VERSION 5.7 ;
  NAMESCASESENSITIVE ON ;
  NOWIREEXTENSIONATPIN ON ;
  DIVIDERCHAR "/" ;
  BUSBITCHARS "[]" ;
UNITS
  DATABASE MICRONS 200 ;
END UNITS

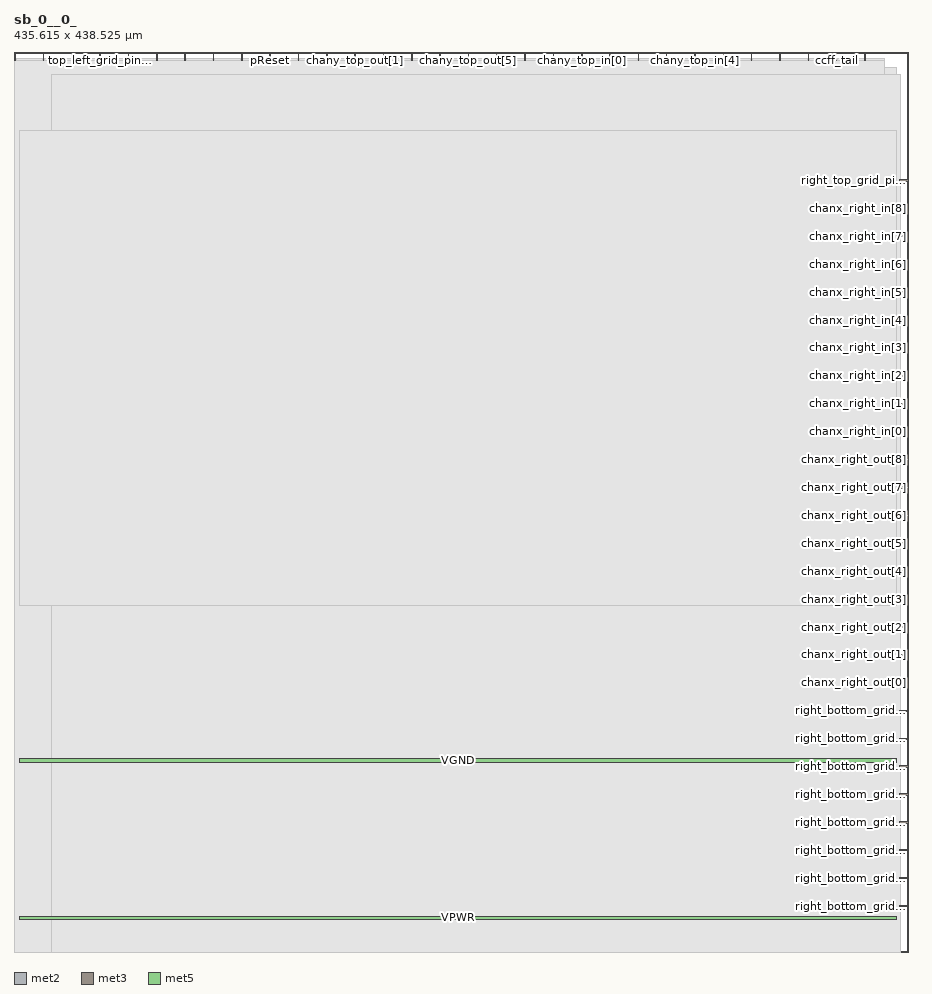
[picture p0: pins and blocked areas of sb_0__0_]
MACRO sb_0__0_
  CLASS BLOCK ;
  FOREIGN sb_0__0_ ;
  ORIGIN 0.000 0.000 ;
  SIZE 435.615 BY 438.525 ;
  PIN ccff_head
    DIRECTION INPUT ;
    PORT
      LAYER met2 ;
        RECT 0.480 434.525 0.760 438.525 ;
    END
  END ccff_head
  PIN top_left_grid_pin_1_
    DIRECTION INPUT ;
    PORT
      LAYER met2 ;
        RECT 14.280 434.525 14.560 438.525 ;
    END
  END top_left_grid_pin_1_
  PIN top_left_grid_pin_3_
    DIRECTION INPUT ;
    PORT
      LAYER met2 ;
        RECT 28.080 434.525 28.360 438.525 ;
    END
  END top_left_grid_pin_3_
  PIN top_left_grid_pin_5_
    DIRECTION INPUT ;
    PORT
      LAYER met2 ;
        RECT 41.880 434.525 42.160 438.525 ;
    END
  END top_left_grid_pin_5_
  PIN top_left_grid_pin_7_
    DIRECTION INPUT ;
    PORT
      LAYER met2 ;
        RECT 55.680 434.525 55.960 438.525 ;
    END
  END top_left_grid_pin_7_
  PIN top_left_grid_pin_9_
    DIRECTION INPUT ;
    PORT
      LAYER met2 ;
        RECT 69.480 434.525 69.760 438.525 ;
    END
  END top_left_grid_pin_9_
  PIN top_left_grid_pin_11_
    DIRECTION INPUT ;
    PORT
      LAYER met2 ;
        RECT 83.280 434.525 83.560 438.525 ;
    END
  END top_left_grid_pin_11_
  PIN top_left_grid_pin_13_
    DIRECTION INPUT ;
    PORT
      LAYER met2 ;
        RECT 97.080 434.525 97.360 438.525 ;
    END
  END top_left_grid_pin_13_
  PIN top_left_grid_pin_15_
    DIRECTION OUTPUT TRISTATE ;
    PORT
      LAYER met2 ;
        RECT 110.880 434.525 111.160 438.525 ;
    END
  END top_left_grid_pin_15_
  PIN pReset
    DIRECTION INPUT ;
    PORT
      LAYER met2 ;
        RECT 124.680 434.525 124.960 438.525 ;
    END
  END pReset
  PIN prog_clk
    DIRECTION INPUT ;
    PORT
      LAYER met2 ;
        RECT 138.480 434.525 138.760 438.525 ;
    END
  END prog_clk
  PIN chany_top_out[0]
    DIRECTION OUTPUT TRISTATE ;
    PORT
      LAYER met2 ;
        RECT 152.280 434.525 152.560 438.525 ;
    END
  END chany_top_out[0]
  PIN chany_top_out[1]
    DIRECTION OUTPUT TRISTATE ;
    PORT
      LAYER met2 ;
        RECT 166.080 434.525 166.360 438.525 ;
    END
  END chany_top_out[1]
  PIN chany_top_out[2]
    DIRECTION OUTPUT TRISTATE ;
    PORT
      LAYER met2 ;
        RECT 179.880 434.525 180.160 438.525 ;
    END
  END chany_top_out[2]
  PIN chany_top_out[3]
    DIRECTION OUTPUT TRISTATE ;
    PORT
      LAYER met2 ;
        RECT 193.680 434.525 193.960 438.525 ;
    END
  END chany_top_out[3]
  PIN chany_top_out[4]
    DIRECTION OUTPUT TRISTATE ;
    PORT
      LAYER met2 ;
        RECT 207.480 434.525 207.760 438.525 ;
    END
  END chany_top_out[4]
  PIN chany_top_out[5]
    DIRECTION OUTPUT TRISTATE ;
    PORT
      LAYER met2 ;
        RECT 221.280 434.525 221.560 438.525 ;
    END
  END chany_top_out[5]
  PIN chany_top_out[6]
    DIRECTION OUTPUT TRISTATE ;
    PORT
      LAYER met2 ;
        RECT 235.080 434.525 235.360 438.525 ;
    END
  END chany_top_out[6]
  PIN chany_top_out[7]
    DIRECTION OUTPUT TRISTATE ;
    PORT
      LAYER met2 ;
        RECT 248.880 434.525 249.160 438.525 ;
    END
  END chany_top_out[7]
  PIN chany_top_out[8]
    DIRECTION OUTPUT TRISTATE ;
    PORT
      LAYER met2 ;
        RECT 262.680 434.525 262.960 438.525 ;
    END
  END chany_top_out[8]
  PIN chany_top_in[0]
    DIRECTION INPUT ;
    PORT
      LAYER met2 ;
        RECT 276.480 434.525 276.760 438.525 ;
    END
  END chany_top_in[0]
  PIN chany_top_in[1]
    DIRECTION INPUT ;
    PORT
      LAYER met2 ;
        RECT 290.280 434.525 290.560 438.525 ;
    END
  END chany_top_in[1]
  PIN chany_top_in[2]
    DIRECTION INPUT ;
    PORT
      LAYER met2 ;
        RECT 304.080 434.525 304.360 438.525 ;
    END
  END chany_top_in[2]
  PIN chany_top_in[3]
    DIRECTION INPUT ;
    PORT
      LAYER met2 ;
        RECT 317.880 434.525 318.160 438.525 ;
    END
  END chany_top_in[3]
  PIN chany_top_in[4]
    DIRECTION INPUT ;
    PORT
      LAYER met2 ;
        RECT 331.680 434.525 331.960 438.525 ;
    END
  END chany_top_in[4]
  PIN chany_top_in[5]
    DIRECTION INPUT ;
    PORT
      LAYER met2 ;
        RECT 345.480 434.525 345.760 438.525 ;
    END
  END chany_top_in[5]
  PIN chany_top_in[6]
    DIRECTION INPUT ;
    PORT
      LAYER met2 ;
        RECT 359.280 434.525 359.560 438.525 ;
    END
  END chany_top_in[6]
  PIN chany_top_in[7]
    DIRECTION INPUT ;
    PORT
      LAYER met2 ;
        RECT 373.080 434.525 373.360 438.525 ;
    END
  END chany_top_in[7]
  PIN chany_top_in[8]
    DIRECTION INPUT ;
    PORT
      LAYER met2 ;
        RECT 386.880 434.525 387.160 438.525 ;
    END
  END chany_top_in[8]
  PIN ccff_tail
    DIRECTION OUTPUT TRISTATE ;
    PORT
      LAYER met2 ;
        RECT 400.680 434.525 400.960 438.525 ;
    END
  END ccff_tail
  PIN top_right_grid_pin_11_
    DIRECTION INPUT ;
    PORT
      LAYER met2 ;
        RECT 414.480 434.525 414.760 438.525 ;
    END
  END top_right_grid_pin_11_
  PIN right_bottom_grid_pin_1_
    DIRECTION INPUT ;
    PORT
      LAYER met3 ;
        RECT 431.615 22.040 435.615 22.640 ;
    END
  END right_bottom_grid_pin_1_
  PIN right_bottom_grid_pin_3_
    DIRECTION INPUT ;
    PORT
      LAYER met3 ;
        RECT 431.615 35.640 435.615 36.240 ;
    END
  END right_bottom_grid_pin_3_
  PIN right_bottom_grid_pin_5_
    DIRECTION INPUT ;
    PORT
      LAYER met3 ;
        RECT 431.615 49.240 435.615 49.840 ;
    END
  END right_bottom_grid_pin_5_
  PIN right_bottom_grid_pin_7_
    DIRECTION INPUT ;
    PORT
      LAYER met3 ;
        RECT 431.615 62.840 435.615 63.440 ;
    END
  END right_bottom_grid_pin_7_
  PIN right_bottom_grid_pin_9_
    DIRECTION INPUT ;
    PORT
      LAYER met3 ;
        RECT 431.615 76.440 435.615 77.040 ;
    END
  END right_bottom_grid_pin_9_
  PIN right_bottom_grid_pin_11_
    DIRECTION INPUT ;
    PORT
      LAYER met3 ;
        RECT 431.615 90.040 435.615 90.640 ;
    END
  END right_bottom_grid_pin_11_
  PIN right_bottom_grid_pin_13_
    DIRECTION INPUT ;
    PORT
      LAYER met3 ;
        RECT 431.615 103.640 435.615 104.240 ;
    END
  END right_bottom_grid_pin_13_
  PIN right_bottom_grid_pin_15_
    DIRECTION INPUT ;
    PORT
      LAYER met3 ;
        RECT 431.615 117.240 435.615 117.840 ;
    END
  END right_bottom_grid_pin_15_
  PIN chanx_right_out[0]
    DIRECTION OUTPUT TRISTATE ;
    PORT
      LAYER met3 ;
        RECT 431.615 130.840 435.615 131.440 ;
    END
  END chanx_right_out[0]
  PIN chanx_right_out[1]
    DIRECTION OUTPUT TRISTATE ;
    PORT
      LAYER met3 ;
        RECT 431.615 144.440 435.615 145.040 ;
    END
  END chanx_right_out[1]
  PIN chanx_right_out[2]
    DIRECTION OUTPUT TRISTATE ;
    PORT
      LAYER met3 ;
        RECT 431.615 158.040 435.615 158.640 ;
    END
  END chanx_right_out[2]
  PIN chanx_right_out[3]
    DIRECTION OUTPUT TRISTATE ;
    PORT
      LAYER met3 ;
        RECT 431.615 171.640 435.615 172.240 ;
    END
  END chanx_right_out[3]
  PIN chanx_right_out[4]
    DIRECTION OUTPUT TRISTATE ;
    PORT
      LAYER met3 ;
        RECT 431.615 185.240 435.615 185.840 ;
    END
  END chanx_right_out[4]
  PIN chanx_right_out[5]
    DIRECTION OUTPUT TRISTATE ;
    PORT
      LAYER met3 ;
        RECT 431.615 198.840 435.615 199.440 ;
    END
  END chanx_right_out[5]
  PIN chanx_right_out[6]
    DIRECTION OUTPUT TRISTATE ;
    PORT
      LAYER met3 ;
        RECT 431.615 212.440 435.615 213.040 ;
    END
  END chanx_right_out[6]
  PIN chanx_right_out[7]
    DIRECTION OUTPUT TRISTATE ;
    PORT
      LAYER met3 ;
        RECT 431.615 226.040 435.615 226.640 ;
    END
  END chanx_right_out[7]
  PIN chanx_right_out[8]
    DIRECTION OUTPUT TRISTATE ;
    PORT
      LAYER met3 ;
        RECT 431.615 239.640 435.615 240.240 ;
    END
  END chanx_right_out[8]
  PIN chanx_right_in[0]
    DIRECTION INPUT ;
    PORT
      LAYER met3 ;
        RECT 431.615 253.240 435.615 253.840 ;
    END
  END chanx_right_in[0]
  PIN chanx_right_in[1]
    DIRECTION INPUT ;
    PORT
      LAYER met3 ;
        RECT 431.615 266.840 435.615 267.440 ;
    END
  END chanx_right_in[1]
  PIN chanx_right_in[2]
    DIRECTION INPUT ;
    PORT
      LAYER met3 ;
        RECT 431.615 280.440 435.615 281.040 ;
    END
  END chanx_right_in[2]
  PIN chanx_right_in[3]
    DIRECTION INPUT ;
    PORT
      LAYER met3 ;
        RECT 431.615 294.040 435.615 294.640 ;
    END
  END chanx_right_in[3]
  PIN chanx_right_in[4]
    DIRECTION INPUT ;
    PORT
      LAYER met3 ;
        RECT 431.615 307.640 435.615 308.240 ;
    END
  END chanx_right_in[4]
  PIN chanx_right_in[5]
    DIRECTION INPUT ;
    PORT
      LAYER met3 ;
        RECT 431.615 321.240 435.615 321.840 ;
    END
  END chanx_right_in[5]
  PIN chanx_right_in[6]
    DIRECTION INPUT ;
    PORT
      LAYER met3 ;
        RECT 431.615 334.840 435.615 335.440 ;
    END
  END chanx_right_in[6]
  PIN chanx_right_in[7]
    DIRECTION INPUT ;
    PORT
      LAYER met3 ;
        RECT 431.615 348.440 435.615 349.040 ;
    END
  END chanx_right_in[7]
  PIN chanx_right_in[8]
    DIRECTION INPUT ;
    PORT
      LAYER met3 ;
        RECT 431.615 362.040 435.615 362.640 ;
    END
  END chanx_right_in[8]
  PIN right_top_grid_pin_10_
    DIRECTION INPUT ;
    PORT
      LAYER met3 ;
        RECT 431.615 375.640 435.615 376.240 ;
    END
  END right_top_grid_pin_10_
  PIN VPWR
    DIRECTION INPUT ;
    USE POWER ;
    PORT
      LAYER met5 ;
        RECT 2.690 15.850 430.030 17.450 ;
    END
  END VPWR
  PIN VGND
    DIRECTION INPUT ;
    USE GROUND ;
    PORT
      LAYER met5 ;
        RECT 2.690 92.440 430.030 94.040 ;
    END
  END VGND
  OBS
      LAYER li1 ;
        RECT 2.690 0.155 430.030 427.365 ;
      LAYER met1 ;
        RECT 0.000 0.000 430.030 430.980 ;
      LAYER met2 ;
        RECT 0.030 434.245 0.200 435.170 ;
        RECT 1.040 434.245 14.000 435.170 ;
        RECT 14.840 434.245 27.800 435.170 ;
        RECT 28.640 434.245 41.600 435.170 ;
        RECT 42.440 434.245 55.400 435.170 ;
        RECT 56.240 434.245 69.200 435.170 ;
        RECT 70.040 434.245 83.000 435.170 ;
        RECT 83.840 434.245 96.800 435.170 ;
        RECT 97.640 434.245 110.600 435.170 ;
        RECT 111.440 434.245 124.400 435.170 ;
        RECT 125.240 434.245 138.200 435.170 ;
        RECT 139.040 434.245 152.000 435.170 ;
        RECT 152.840 434.245 165.800 435.170 ;
        RECT 166.640 434.245 179.600 435.170 ;
        RECT 180.440 434.245 193.400 435.170 ;
        RECT 194.240 434.245 207.200 435.170 ;
        RECT 208.040 434.245 221.000 435.170 ;
        RECT 221.840 434.245 234.800 435.170 ;
        RECT 235.640 434.245 248.600 435.170 ;
        RECT 249.440 434.245 262.400 435.170 ;
        RECT 263.240 434.245 276.200 435.170 ;
        RECT 277.040 434.245 290.000 435.170 ;
        RECT 290.840 434.245 303.800 435.170 ;
        RECT 304.640 434.245 317.600 435.170 ;
        RECT 318.440 434.245 331.400 435.170 ;
        RECT 332.240 434.245 345.200 435.170 ;
        RECT 346.040 434.245 359.000 435.170 ;
        RECT 359.840 434.245 372.800 435.170 ;
        RECT 373.640 434.245 386.600 435.170 ;
        RECT 387.440 434.245 400.400 435.170 ;
        RECT 401.240 434.245 414.200 435.170 ;
        RECT 415.040 434.245 423.960 435.170 ;
        RECT 0.030 0.000 423.960 434.245 ;
      LAYER met3 ;
        RECT 18.210 376.640 432.060 427.445 ;
        RECT 18.210 375.240 431.215 376.640 ;
        RECT 18.210 363.040 432.060 375.240 ;
        RECT 18.210 361.640 431.215 363.040 ;
        RECT 18.210 349.440 432.060 361.640 ;
        RECT 18.210 348.040 431.215 349.440 ;
        RECT 18.210 335.840 432.060 348.040 ;
        RECT 18.210 334.440 431.215 335.840 ;
        RECT 18.210 322.240 432.060 334.440 ;
        RECT 18.210 320.840 431.215 322.240 ;
        RECT 18.210 308.640 432.060 320.840 ;
        RECT 18.210 307.240 431.215 308.640 ;
        RECT 18.210 295.040 432.060 307.240 ;
        RECT 18.210 293.640 431.215 295.040 ;
        RECT 18.210 281.440 432.060 293.640 ;
        RECT 18.210 280.040 431.215 281.440 ;
        RECT 18.210 267.840 432.060 280.040 ;
        RECT 18.210 266.440 431.215 267.840 ;
        RECT 18.210 254.240 432.060 266.440 ;
        RECT 18.210 252.840 431.215 254.240 ;
        RECT 18.210 240.640 432.060 252.840 ;
        RECT 18.210 239.240 431.215 240.640 ;
        RECT 18.210 227.040 432.060 239.240 ;
        RECT 18.210 225.640 431.215 227.040 ;
        RECT 18.210 213.440 432.060 225.640 ;
        RECT 18.210 212.040 431.215 213.440 ;
        RECT 18.210 199.840 432.060 212.040 ;
        RECT 18.210 198.440 431.215 199.840 ;
        RECT 18.210 186.240 432.060 198.440 ;
        RECT 18.210 184.840 431.215 186.240 ;
        RECT 18.210 172.640 432.060 184.840 ;
        RECT 18.210 171.240 431.215 172.640 ;
        RECT 18.210 159.040 432.060 171.240 ;
        RECT 18.210 157.640 431.215 159.040 ;
        RECT 18.210 145.440 432.060 157.640 ;
        RECT 18.210 144.040 431.215 145.440 ;
        RECT 18.210 131.840 432.060 144.040 ;
        RECT 18.210 130.440 431.215 131.840 ;
        RECT 18.210 118.240 432.060 130.440 ;
        RECT 18.210 116.840 431.215 118.240 ;
        RECT 18.210 104.640 432.060 116.840 ;
        RECT 18.210 103.240 431.215 104.640 ;
        RECT 18.210 91.040 432.060 103.240 ;
        RECT 18.210 89.640 431.215 91.040 ;
        RECT 18.210 77.440 432.060 89.640 ;
        RECT 18.210 76.040 431.215 77.440 ;
        RECT 18.210 63.840 432.060 76.040 ;
        RECT 18.210 62.440 431.215 63.840 ;
        RECT 18.210 50.240 432.060 62.440 ;
        RECT 18.210 48.840 431.215 50.240 ;
        RECT 18.210 36.640 432.060 48.840 ;
        RECT 18.210 35.240 431.215 36.640 ;
        RECT 18.210 23.040 432.060 35.240 ;
        RECT 18.210 21.640 431.215 23.040 ;
        RECT 18.210 0.075 432.060 21.640 ;
      LAYER met4 ;
        RECT 18.210 0.000 432.035 427.520 ;
      LAYER met5 ;
        RECT 2.690 169.030 430.030 400.400 ;
  END
END sb_0__0_
END LIBRARY

